VERSION 5.7 ;
  NAMESCASESENSITIVE ON ;
  NOWIREEXTENSIONATPIN ON ;
  DIVIDERCHAR "/" ;
  BUSBITCHARS "[]" ;
UNITS
  DATABASE MICRONS 200 ;
END UNITS

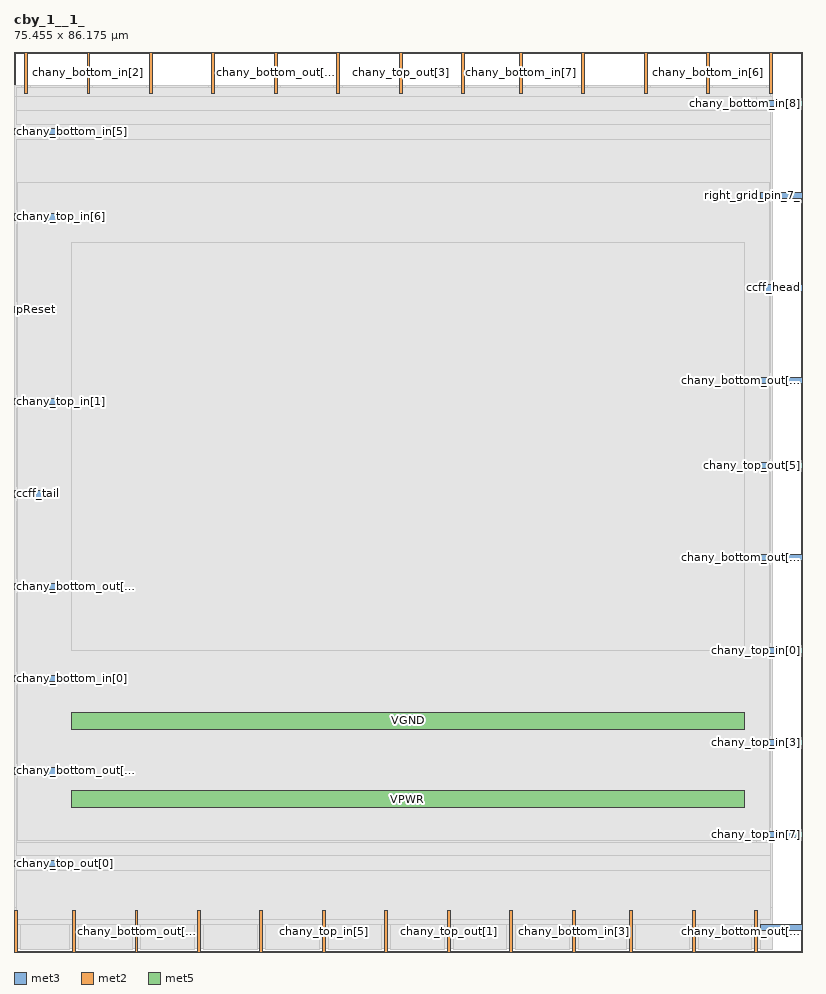
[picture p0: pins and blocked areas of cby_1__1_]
MACRO cby_1__1_
  CLASS BLOCK ;
  FOREIGN cby_1__1_ ;
  ORIGIN 0.000 0.000 ;
  SIZE 75.455 BY 86.175 ;
  PIN ccff_head
    DIRECTION INPUT ;
    PORT
      LAYER met3 ;
        RECT 71.455 63.280 75.455 63.880 ;
    END
  END ccff_head
  PIN ccff_tail
    DIRECTION OUTPUT TRISTATE ;
    PORT
      LAYER met3 ;
        RECT 0.000 43.560 4.000 44.160 ;
    END
  END ccff_tail
  PIN chany_bottom_in[0]
    DIRECTION INPUT ;
    PORT
      LAYER met3 ;
        RECT 0.000 25.880 4.000 26.480 ;
    END
  END chany_bottom_in[0]
  PIN chany_bottom_in[1]
    DIRECTION INPUT ;
    PORT
      LAYER met2 ;
        RECT 0.090 0.000 0.370 4.000 ;
    END
  END chany_bottom_in[1]
  PIN chany_bottom_in[2]
    DIRECTION INPUT ;
    PORT
      LAYER met2 ;
        RECT 6.990 82.175 7.270 86.175 ;
    END
  END chany_bottom_in[2]
  PIN chany_bottom_in[3]
    DIRECTION INPUT ;
    PORT
      LAYER met2 ;
        RECT 53.450 0.000 53.730 4.000 ;
    END
  END chany_bottom_in[3]
  PIN chany_bottom_in[4]
    DIRECTION INPUT ;
    PORT
      LAYER met2 ;
        RECT 64.950 0.000 65.230 4.000 ;
    END
  END chany_bottom_in[4]
  PIN chany_bottom_in[5]
    DIRECTION INPUT ;
    PORT
      LAYER met3 ;
        RECT 0.000 78.240 4.000 78.840 ;
    END
  END chany_bottom_in[5]
  PIN chany_bottom_in[6]
    DIRECTION INPUT ;
    PORT
      LAYER met2 ;
        RECT 66.330 82.175 66.610 86.175 ;
    END
  END chany_bottom_in[6]
  PIN chany_bottom_in[7]
    DIRECTION INPUT ;
    PORT
      LAYER met2 ;
        RECT 48.390 82.175 48.670 86.175 ;
    END
  END chany_bottom_in[7]
  PIN chany_bottom_in[8]
    DIRECTION INPUT ;
    PORT
      LAYER met3 ;
        RECT 71.455 80.960 75.455 81.560 ;
    END
  END chany_bottom_in[8]
  PIN chany_bottom_out[0]
    DIRECTION OUTPUT TRISTATE ;
    PORT
      LAYER met3 ;
        RECT 0.000 17.040 4.000 17.640 ;
    END
  END chany_bottom_out[0]
  PIN chany_bottom_out[1]
    DIRECTION OUTPUT TRISTATE ;
    PORT
      LAYER met2 ;
        RECT 70.930 0.000 71.210 4.000 ;
    END
  END chany_bottom_out[1]
  PIN chany_bottom_out[2]
    DIRECTION OUTPUT TRISTATE ;
    PORT
      LAYER met3 ;
        RECT 0.000 34.720 4.000 35.320 ;
    END
  END chany_bottom_out[2]
  PIN chany_bottom_out[3]
    DIRECTION OUTPUT TRISTATE ;
    PORT
      LAYER met2 ;
        RECT 12.970 82.175 13.250 86.175 ;
    END
  END chany_bottom_out[3]
  PIN chany_bottom_out[4]
    DIRECTION OUTPUT TRISTATE ;
    PORT
      LAYER met2 ;
        RECT 11.590 0.000 11.870 4.000 ;
    END
  END chany_bottom_out[4]
  PIN chany_bottom_out[5]
    DIRECTION OUTPUT TRISTATE ;
    PORT
      LAYER met3 ;
        RECT 71.455 37.440 75.455 38.040 ;
    END
  END chany_bottom_out[5]
  PIN chany_bottom_out[6]
    DIRECTION OUTPUT TRISTATE ;
    PORT
      LAYER met2 ;
        RECT 24.930 82.175 25.210 86.175 ;
    END
  END chany_bottom_out[6]
  PIN chany_bottom_out[7]
    DIRECTION OUTPUT TRISTATE ;
    PORT
      LAYER met3 ;
        RECT 71.455 54.440 75.455 55.040 ;
    END
  END chany_bottom_out[7]
  PIN chany_bottom_out[8]
    DIRECTION OUTPUT TRISTATE ;
    PORT
      LAYER met2 ;
        RECT 60.350 82.175 60.630 86.175 ;
    END
  END chany_bottom_out[8]
  PIN chany_top_in[0]
    DIRECTION INPUT ;
    PORT
      LAYER met3 ;
        RECT 71.455 28.600 75.455 29.200 ;
    END
  END chany_top_in[0]
  PIN chany_top_in[1]
    DIRECTION INPUT ;
    PORT
      LAYER met3 ;
        RECT 0.000 52.400 4.000 53.000 ;
    END
  END chany_top_in[1]
  PIN chany_top_in[2]
    DIRECTION INPUT ;
    PORT
      LAYER met2 ;
        RECT 30.910 82.175 31.190 86.175 ;
    END
  END chany_top_in[2]
  PIN chany_top_in[3]
    DIRECTION INPUT ;
    PORT
      LAYER met3 ;
        RECT 71.455 19.760 75.455 20.360 ;
    END
  END chany_top_in[3]
  PIN chany_top_in[4]
    DIRECTION INPUT ;
    PORT
      LAYER met2 ;
        RECT 1.010 82.175 1.290 86.175 ;
    END
  END chany_top_in[4]
  PIN chany_top_in[5]
    DIRECTION INPUT ;
    PORT
      LAYER met2 ;
        RECT 29.530 0.000 29.810 4.000 ;
    END
  END chany_top_in[5]
  PIN chany_top_in[6]
    DIRECTION INPUT ;
    PORT
      LAYER met3 ;
        RECT 0.000 70.080 4.000 70.680 ;
    END
  END chany_top_in[6]
  PIN chany_top_in[7]
    DIRECTION INPUT ;
    PORT
      LAYER met3 ;
        RECT 71.455 10.920 75.455 11.520 ;
    END
  END chany_top_in[7]
  PIN chany_top_in[8]
    DIRECTION INPUT ;
    PORT
      LAYER met2 ;
        RECT 42.870 82.175 43.150 86.175 ;
    END
  END chany_top_in[8]
  PIN chany_top_out[0]
    DIRECTION OUTPUT TRISTATE ;
    PORT
      LAYER met3 ;
        RECT 0.000 8.200 4.000 8.800 ;
    END
  END chany_top_out[0]
  PIN chany_top_out[1]
    DIRECTION OUTPUT TRISTATE ;
    PORT
      LAYER met2 ;
        RECT 41.490 0.000 41.770 4.000 ;
    END
  END chany_top_out[1]
  PIN chany_top_out[2]
    DIRECTION OUTPUT TRISTATE ;
    PORT
      LAYER met2 ;
        RECT 72.310 82.175 72.590 86.175 ;
    END
  END chany_top_out[2]
  PIN chany_top_out[3]
    DIRECTION OUTPUT TRISTATE ;
    PORT
      LAYER met2 ;
        RECT 36.890 82.175 37.170 86.175 ;
    END
  END chany_top_out[3]
  PIN chany_top_out[4]
    DIRECTION OUTPUT TRISTATE ;
    PORT
      LAYER met2 ;
        RECT 54.370 82.175 54.650 86.175 ;
    END
  END chany_top_out[4]
  PIN chany_top_out[5]
    DIRECTION OUTPUT TRISTATE ;
    PORT
      LAYER met3 ;
        RECT 71.455 46.280 75.455 46.880 ;
    END
  END chany_top_out[5]
  PIN chany_top_out[6]
    DIRECTION OUTPUT TRISTATE ;
    PORT
      LAYER met2 ;
        RECT 23.550 0.000 23.830 4.000 ;
    END
  END chany_top_out[6]
  PIN chany_top_out[7]
    DIRECTION OUTPUT TRISTATE ;
    PORT
      LAYER met2 ;
        RECT 17.570 0.000 17.850 4.000 ;
    END
  END chany_top_out[7]
  PIN chany_top_out[8]
    DIRECTION OUTPUT TRISTATE ;
    PORT
      LAYER met3 ;
        RECT 71.455 2.080 75.455 2.680 ;
    END
  END chany_top_out[8]
  PIN left_grid_pin_1_
    DIRECTION OUTPUT TRISTATE ;
    PORT
      LAYER met2 ;
        RECT 58.970 0.000 59.250 4.000 ;
    END
  END left_grid_pin_1_
  PIN left_grid_pin_5_
    DIRECTION OUTPUT TRISTATE ;
    PORT
      LAYER met2 ;
        RECT 47.470 0.000 47.750 4.000 ;
    END
  END left_grid_pin_5_
  PIN left_grid_pin_9_
    DIRECTION OUTPUT TRISTATE ;
    PORT
      LAYER met2 ;
        RECT 35.510 0.000 35.790 4.000 ;
    END
  END left_grid_pin_9_
  PIN pReset
    DIRECTION INPUT ;
    PORT
      LAYER met3 ;
        RECT 0.000 61.240 4.000 61.840 ;
    END
  END pReset
  PIN prog_clk
    DIRECTION INPUT ;
    PORT
      LAYER met2 ;
        RECT 5.610 0.000 5.890 4.000 ;
    END
  END prog_clk
  PIN right_grid_pin_3_
    DIRECTION OUTPUT TRISTATE ;
    PORT
      LAYER met2 ;
        RECT 18.950 82.175 19.230 86.175 ;
    END
  END right_grid_pin_3_
  PIN right_grid_pin_7_
    DIRECTION OUTPUT TRISTATE ;
    PORT
      LAYER met3 ;
        RECT 71.455 72.120 75.455 72.720 ;
    END
  END right_grid_pin_7_
  PIN VPWR
    DIRECTION INPUT ;
    USE POWER ;
    PORT
      LAYER met5 ;
        RECT 5.520 13.840 69.920 15.440 ;
    END
  END VPWR
  PIN VGND
    DIRECTION INPUT ;
    USE GROUND ;
    PORT
      LAYER met5 ;
        RECT 5.520 21.340 69.920 22.940 ;
    END
  END VGND
  OBS
      LAYER li1 ;
        RECT 5.520 10.795 69.920 73.525 ;
      LAYER met1 ;
        RECT 0.070 0.380 72.610 82.920 ;
      LAYER met2 ;
        RECT 0.090 81.895 0.730 82.950 ;
        RECT 1.570 81.895 6.710 82.950 ;
        RECT 7.550 81.895 12.690 82.950 ;
        RECT 13.530 81.895 18.670 82.950 ;
        RECT 19.510 81.895 24.650 82.950 ;
        RECT 25.490 81.895 30.630 82.950 ;
        RECT 31.470 81.895 36.610 82.950 ;
        RECT 37.450 81.895 42.590 82.950 ;
        RECT 43.430 81.895 48.110 82.950 ;
        RECT 48.950 81.895 54.090 82.950 ;
        RECT 54.930 81.895 60.070 82.950 ;
        RECT 60.910 81.895 66.050 82.950 ;
        RECT 66.890 81.895 72.030 82.950 ;
        RECT 0.090 4.280 72.590 81.895 ;
        RECT 0.650 0.270 5.330 4.280 ;
        RECT 6.170 0.270 11.310 4.280 ;
        RECT 12.150 0.270 17.290 4.280 ;
        RECT 18.130 0.270 23.270 4.280 ;
        RECT 24.110 0.270 29.250 4.280 ;
        RECT 30.090 0.270 35.230 4.280 ;
        RECT 36.070 0.270 41.210 4.280 ;
        RECT 42.050 0.270 47.190 4.280 ;
        RECT 48.030 0.270 53.170 4.280 ;
        RECT 54.010 0.270 58.690 4.280 ;
        RECT 59.530 0.270 64.670 4.280 ;
        RECT 65.510 0.270 70.650 4.280 ;
        RECT 71.490 0.270 72.590 4.280 ;
      LAYER met3 ;
        RECT 0.270 81.960 72.410 82.785 ;
        RECT 0.270 80.560 71.055 81.960 ;
        RECT 0.270 79.240 72.410 80.560 ;
        RECT 4.400 77.840 72.410 79.240 ;
        RECT 0.270 73.120 72.410 77.840 ;
        RECT 0.270 71.720 71.055 73.120 ;
        RECT 0.270 71.080 72.410 71.720 ;
        RECT 4.400 69.680 72.410 71.080 ;
        RECT 0.270 64.280 72.410 69.680 ;
        RECT 0.270 62.880 71.055 64.280 ;
        RECT 0.270 62.240 72.410 62.880 ;
        RECT 4.400 60.840 72.410 62.240 ;
        RECT 0.270 55.440 72.410 60.840 ;
        RECT 0.270 54.040 71.055 55.440 ;
        RECT 0.270 53.400 72.410 54.040 ;
        RECT 4.400 52.000 72.410 53.400 ;
        RECT 0.270 47.280 72.410 52.000 ;
        RECT 0.270 45.880 71.055 47.280 ;
        RECT 0.270 44.560 72.410 45.880 ;
        RECT 4.400 43.160 72.410 44.560 ;
        RECT 0.270 38.440 72.410 43.160 ;
        RECT 0.270 37.040 71.055 38.440 ;
        RECT 0.270 35.720 72.410 37.040 ;
        RECT 4.400 34.320 72.410 35.720 ;
        RECT 0.270 29.600 72.410 34.320 ;
        RECT 0.270 28.200 71.055 29.600 ;
        RECT 0.270 26.880 72.410 28.200 ;
        RECT 4.400 25.480 72.410 26.880 ;
        RECT 0.270 20.760 72.410 25.480 ;
        RECT 0.270 19.360 71.055 20.760 ;
        RECT 0.270 18.040 72.410 19.360 ;
        RECT 4.400 16.640 72.410 18.040 ;
        RECT 0.270 11.920 72.410 16.640 ;
        RECT 0.270 10.520 71.055 11.920 ;
        RECT 0.270 9.200 72.410 10.520 ;
        RECT 4.400 7.800 72.410 9.200 ;
        RECT 0.270 3.080 72.410 7.800 ;
        RECT 0.270 2.680 71.055 3.080 ;
      LAYER met4 ;
        RECT 0.295 10.640 72.385 73.680 ;
      LAYER met5 ;
        RECT 5.520 28.840 69.920 67.940 ;
  END
END cby_1__1_
END LIBRARY

